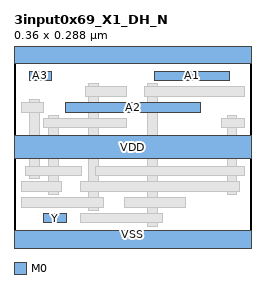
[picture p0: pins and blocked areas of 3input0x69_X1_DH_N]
MACRO 3input0x69_X1_DH_N
  CLASS CORE ;
  ORIGIN 0 0 ;
  FOREIGN 3input0x69_X1_DH_N 0 0 ;
  SIZE 0.3600 BY 0.2880 ;
  SYMMETRY X Y ;
  SITE coresite ;
  PIN A1
    DIRECTION INPUT ;
    USE SIGNAL ;
    PORT
      LAYER M0 ;
        RECT 0.2130 0.2450 0.3270 0.2590 ;
    END
  END A1
  PIN A2
    DIRECTION INPUT ;
    USE SIGNAL ;
    PORT
      LAYER M0 ;
        RECT 0.0780 0.1970 0.2820 0.2110 ;
    END
  END A2
  PIN A3
    DIRECTION INPUT ;
    USE SIGNAL ;
    PORT
      LAYER M0 ;
        RECT 0.0230 0.2450 0.0570 0.2590 ;
    END
  END A3
  PIN Y
    DIRECTION OUTPUT ;
    USE SIGNAL ;
    PORT
      LAYER M0 ;
        RECT 0.0450 0.0290 0.0800 0.0430 ;
    END
  END Y
  PIN VDD
    DIRECTION INOUT ;
    USE POWER ;
    SHAPE ABUTMENT ;
    PORT
      LAYER M0 ;
        RECT 0.0000 0.1260 0.3600 0.1620 ;
    END
  END VDD
  PIN VSS
    DIRECTION INOUT ;
    USE GROUND ;
    SHAPE ABUTMENT ;
    PORT
      LAYER M0 ;
        RECT 0.0000 -0.0180 0.3600 0.0180 ;
        RECT 0.0000 0.2700 0.3600 0.3060 ;
    END
  END VSS
  OBS
    LAYER M1 ;
      RECT 0.0530 0.0720 0.0680 0.1920 ;
      RECT 0.3230 0.0720 0.3380 0.1920 ;
      RECT 0.0230 0.0960 0.0380 0.2160 ;
      RECT 0.1130 0.0480 0.1280 0.2400 ;
      RECT 0.2030 0.0240 0.2180 0.2400 ;
    LAYER V0 ;
      RECT 0.0230 0.1010 0.0370 0.1150 ;
      RECT 0.0230 0.1970 0.0370 0.2110 ;
      RECT 0.0530 0.0770 0.0670 0.0910 ;
      RECT 0.0530 0.1730 0.0670 0.1870 ;
      RECT 0.3230 0.0770 0.3370 0.0910 ;
      RECT 0.3230 0.1730 0.3370 0.1870 ;
      RECT 0.1130 0.0530 0.1270 0.0670 ;
      RECT 0.1130 0.2210 0.1270 0.2350 ;
      RECT 0.2030 0.0290 0.2170 0.0430 ;
      RECT 0.2030 0.2210 0.2170 0.2350 ;
    LAYER M0 ;
      RECT 0.1010 0.0290 0.2250 0.0430 ;
      RECT 0.0110 0.0530 0.1350 0.0670 ;
      RECT 0.1680 0.0530 0.2600 0.0670 ;
      RECT 0.0110 0.0770 0.0720 0.0910 ;
      RECT 0.1010 0.0770 0.3420 0.0910 ;
      RECT 0.0180 0.1010 0.1020 0.1150 ;
      RECT 0.1230 0.1010 0.3500 0.1150 ;
      RECT 0.0450 0.1730 0.1700 0.1870 ;
      RECT 0.3150 0.1730 0.3500 0.1870 ;
      RECT 0.0110 0.1970 0.0450 0.2110 ;
      RECT 0.1080 0.2210 0.1700 0.2350 ;
      RECT 0.1980 0.2210 0.3500 0.2350 ;
  END
END 3input0x69_X1_DH_N
